VERSION 5.8 ;
BUSBITCHARS "[]" ;
DIVIDERCHAR "/" ;

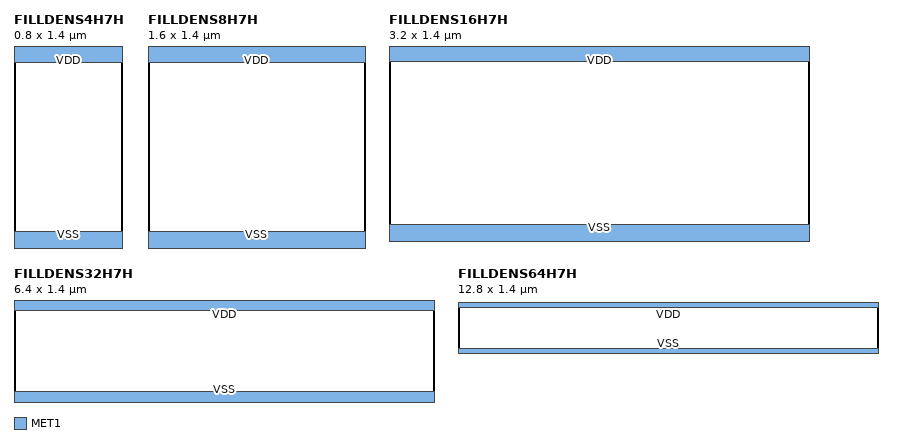
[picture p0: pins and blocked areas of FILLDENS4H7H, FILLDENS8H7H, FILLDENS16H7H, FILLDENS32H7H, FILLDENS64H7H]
MACRO FILLDENS4H7H
  CLASS CORE ;
  ORIGIN 0 0 ;
  FOREIGN FILLDENS4H7H 0 0 ;
  SIZE 0.8 BY 1.4 ;
  SYMMETRY X Y ;
  SITE core7 ;
  PIN VDD
    DIRECTION INOUT ;
    USE POWER ;
    SHAPE ABUTMENT ;
    PORT
      LAYER MET1 ;
        RECT 0 1.32 0.8 1.48 ;
    END
  END VDD
  PIN VSS
    DIRECTION INOUT ;
    USE GROUND ;
    SHAPE ABUTMENT ;
    PORT
      LAYER MET1 ;
        RECT 0 -0.08 0.8 0.08 ;
    END
  END VSS
END FILLDENS4H7H

MACRO FILLDENS8H7H
  CLASS CORE ;
  ORIGIN 0 0 ;
  FOREIGN FILLDENS8H7H 0 0 ;
  SIZE 1.6 BY 1.4 ;
  SYMMETRY X Y ;
  SITE core7 ;
  PIN VDD
    DIRECTION INOUT ;
    USE POWER ;
    SHAPE ABUTMENT ;
    PORT
      LAYER MET1 ;
        RECT 0 1.32 1.6 1.48 ;
    END
  END VDD
  PIN VSS
    DIRECTION INOUT ;
    USE GROUND ;
    SHAPE ABUTMENT ;
    PORT
      LAYER MET1 ;
        RECT 0 -0.08 1.6 0.08 ;
    END
  END VSS
END FILLDENS8H7H

MACRO FILLDENS16H7H
  CLASS CORE ;
  ORIGIN 0 0 ;
  FOREIGN FILLDENS16H7H 0 0 ;
  SIZE 3.2 BY 1.4 ;
  SYMMETRY X Y ;
  SITE core7 ;
  PIN VDD
    DIRECTION INOUT ;
    USE POWER ;
    SHAPE ABUTMENT ;
    PORT
      LAYER MET1 ;
        RECT 0 1.32 3.2 1.48 ;
    END
  END VDD
  PIN VSS
    DIRECTION INOUT ;
    USE GROUND ;
    SHAPE ABUTMENT ;
    PORT
      LAYER MET1 ;
        RECT 0 -0.08 3.2 0.08 ;
    END
  END VSS
END FILLDENS16H7H

MACRO FILLDENS32H7H
  CLASS CORE ;
  ORIGIN 0 0 ;
  FOREIGN FILLDENS32H7H 0 0 ;
  SIZE 6.4 BY 1.4 ;
  SYMMETRY X Y ;
  SITE core7 ;
  PIN VDD
    DIRECTION INOUT ;
    USE POWER ;
    SHAPE ABUTMENT ;
    PORT
      LAYER MET1 ;
        RECT 0 1.32 6.4 1.48 ;
    END
  END VDD
  PIN VSS
    DIRECTION INOUT ;
    USE GROUND ;
    SHAPE ABUTMENT ;
    PORT
      LAYER MET1 ;
        RECT 0 -0.08 6.4 0.08 ;
    END
  END VSS
END FILLDENS32H7H

MACRO FILLDENS64H7H
  CLASS CORE ;
  ORIGIN 0 0 ;
  FOREIGN FILLDENS64H7H 0 0 ;
  SIZE 12.8 BY 1.4 ;
  SYMMETRY X Y ;
  SITE core7 ;
  PIN VDD
    DIRECTION INOUT ;
    USE POWER ;
    SHAPE ABUTMENT ;
    PORT
      LAYER MET1 ;
        RECT 0 1.32 12.8 1.48 ;
    END
  END VDD
  PIN VSS
    DIRECTION INOUT ;
    USE GROUND ;
    SHAPE ABUTMENT ;
    PORT
      LAYER MET1 ;
        RECT 0 -0.08 12.8 0.08 ;
    END
  END VSS
END FILLDENS64H7H

END LIBRARY
